VERSION 5.7 ;
  NOWIREEXTENSIONATPIN ON ;
  DIVIDERCHAR "/" ;
  BUSBITCHARS "[]" ;
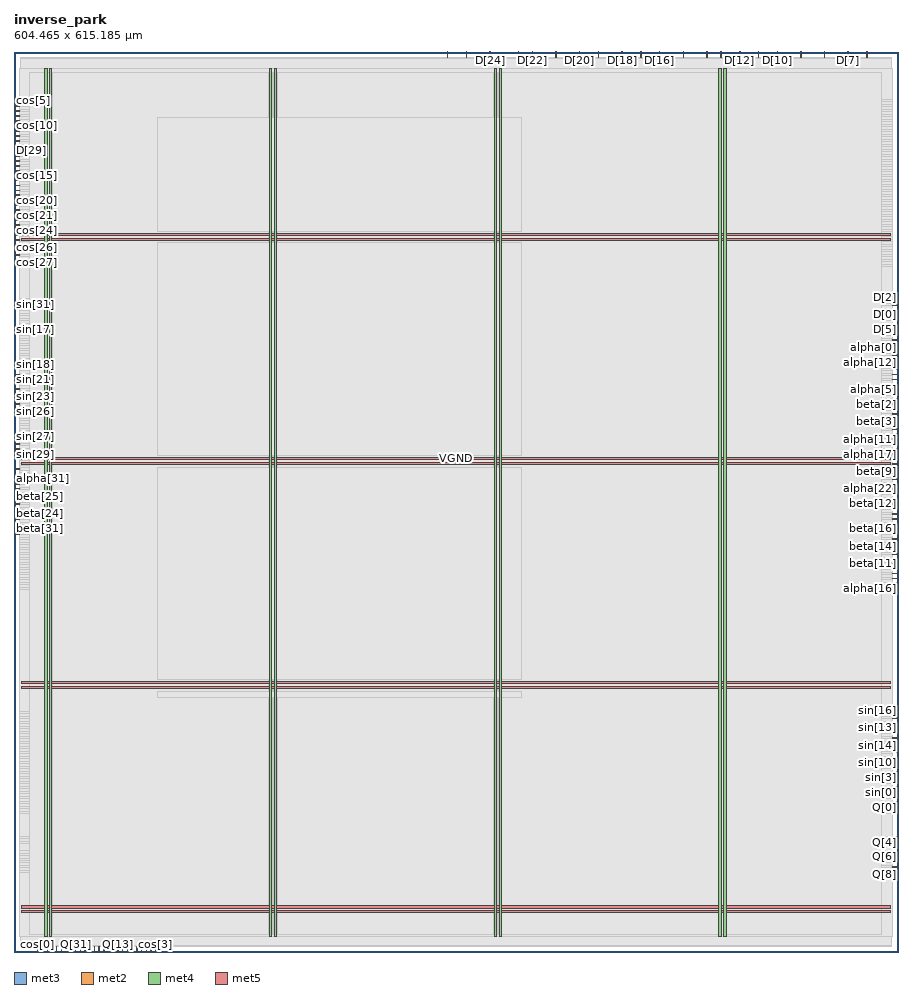
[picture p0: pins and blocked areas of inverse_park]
MACRO inverse_park
  CLASS BLOCK ;
  FOREIGN inverse_park ;
  ORIGIN 0.000 0.000 ;
  SIZE 604.465 BY 615.185 ;
  PIN D[0]
    DIRECTION INPUT ;
    USE SIGNAL ;
    ANTENNAGATEAREA 0.196500 ;
    PORT
      LAYER met3 ;
        RECT 600.465 435.240 604.465 435.840 ;
    END
  END D[0]
  PIN D[10]
    DIRECTION INPUT ;
    USE SIGNAL ;
    ANTENNAGATEAREA 0.159000 ;
    PORT
      LAYER met2 ;
        RECT 521.730 611.185 522.010 615.185 ;
    END
  END D[10]
  PIN D[11]
    DIRECTION INPUT ;
    USE SIGNAL ;
    ANTENNAGATEAREA 0.247500 ;
    PORT
      LAYER met2 ;
        RECT 508.850 611.185 509.130 615.185 ;
    END
  END D[11]
  PIN D[12]
    DIRECTION INPUT ;
    USE SIGNAL ;
    ANTENNAGATEAREA 0.247500 ;
    PORT
      LAYER met2 ;
        RECT 495.970 611.185 496.250 615.185 ;
    END
  END D[12]
  PIN D[13]
    DIRECTION INPUT ;
    USE SIGNAL ;
    ANTENNAGATEAREA 0.159000 ;
    PORT
      LAYER met2 ;
        RECT 483.090 611.185 483.370 615.185 ;
    END
  END D[13]
  PIN D[14]
    DIRECTION INPUT ;
    USE SIGNAL ;
    ANTENNAGATEAREA 0.213000 ;
    PORT
      LAYER met2 ;
        RECT 473.430 611.185 473.710 615.185 ;
    END
  END D[14]
  PIN D[15]
    DIRECTION INPUT ;
    USE SIGNAL ;
    ANTENNAGATEAREA 0.247500 ;
    PORT
      LAYER met2 ;
        RECT 457.330 611.185 457.610 615.185 ;
    END
  END D[15]
  PIN D[16]
    DIRECTION INPUT ;
    USE SIGNAL ;
    ANTENNAGATEAREA 0.159000 ;
    PORT
      LAYER met2 ;
        RECT 441.230 611.185 441.510 615.185 ;
    END
  END D[16]
  PIN D[17]
    DIRECTION INPUT ;
    USE SIGNAL ;
    ANTENNAGATEAREA 0.159000 ;
    PORT
      LAYER met2 ;
        RECT 428.350 611.185 428.630 615.185 ;
    END
  END D[17]
  PIN D[18]
    DIRECTION INPUT ;
    USE SIGNAL ;
    ANTENNAGATEAREA 0.159000 ;
    PORT
      LAYER met2 ;
        RECT 415.470 611.185 415.750 615.185 ;
    END
  END D[18]
  PIN D[19]
    DIRECTION INPUT ;
    USE SIGNAL ;
    ANTENNAGATEAREA 0.213000 ;
    PORT
      LAYER met2 ;
        RECT 399.370 611.185 399.650 615.185 ;
    END
  END D[19]
  PIN D[1]
    DIRECTION INPUT ;
    USE SIGNAL ;
    ANTENNAGATEAREA 0.159000 ;
    PORT
      LAYER met3 ;
        RECT 600.465 431.840 604.465 432.440 ;
    END
  END D[1]
  PIN D[20]
    DIRECTION INPUT ;
    USE SIGNAL ;
    ANTENNAGATEAREA 0.196500 ;
    PORT
      LAYER met2 ;
        RECT 386.490 611.185 386.770 615.185 ;
    END
  END D[20]
  PIN D[21]
    DIRECTION INPUT ;
    USE SIGNAL ;
    ANTENNAGATEAREA 0.196500 ;
    PORT
      LAYER met2 ;
        RECT 370.390 611.185 370.670 615.185 ;
    END
  END D[21]
  PIN D[22]
    DIRECTION INPUT ;
    USE SIGNAL ;
    ANTENNAGATEAREA 0.196500 ;
    PORT
      LAYER met2 ;
        RECT 354.290 611.185 354.570 615.185 ;
    END
  END D[22]
  PIN D[23]
    DIRECTION INPUT ;
    USE SIGNAL ;
    ANTENNAGATEAREA 0.196500 ;
    PORT
      LAYER met2 ;
        RECT 344.630 611.185 344.910 615.185 ;
    END
  END D[23]
  PIN D[24]
    DIRECTION INPUT ;
    USE SIGNAL ;
    ANTENNAGATEAREA 0.213000 ;
    PORT
      LAYER met2 ;
        RECT 325.310 611.185 325.590 615.185 ;
    END
  END D[24]
  PIN D[25]
    DIRECTION INPUT ;
    USE SIGNAL ;
    ANTENNAGATEAREA 0.213000 ;
    PORT
      LAYER met3 ;
        RECT 0.000 578.040 4.000 578.640 ;
    END
  END D[25]
  PIN D[26]
    DIRECTION INPUT ;
    USE SIGNAL ;
    ANTENNAGATEAREA 0.196500 ;
    PORT
      LAYER met3 ;
        RECT 0.000 574.640 4.000 575.240 ;
    END
  END D[26]
  PIN D[27]
    DIRECTION INPUT ;
    USE SIGNAL ;
    ANTENNAGATEAREA 0.196500 ;
    PORT
      LAYER met3 ;
        RECT 0.000 567.840 4.000 568.440 ;
    END
  END D[27]
  PIN D[28]
    DIRECTION INPUT ;
    USE SIGNAL ;
    ANTENNAGATEAREA 0.196500 ;
    PORT
      LAYER met3 ;
        RECT 0.000 557.640 4.000 558.240 ;
    END
  END D[28]
  PIN D[29]
    DIRECTION INPUT ;
    USE SIGNAL ;
    ANTENNAGATEAREA 0.159000 ;
    PORT
      LAYER met3 ;
        RECT 0.000 547.440 4.000 548.040 ;
    END
  END D[29]
  PIN D[2]
    DIRECTION INPUT ;
    USE SIGNAL ;
    ANTENNAGATEAREA 0.213000 ;
    PORT
      LAYER met3 ;
        RECT 600.465 442.040 604.465 442.640 ;
    END
  END D[2]
  PIN D[30]
    DIRECTION INPUT ;
    USE SIGNAL ;
    ANTENNAGATEAREA 0.196500 ;
    PORT
      LAYER met3 ;
        RECT 0.000 537.240 4.000 537.840 ;
    END
  END D[30]
  PIN D[31]
    DIRECTION INPUT ;
    USE SIGNAL ;
    ANTENNAGATEAREA 0.196500 ;
    PORT
      LAYER met3 ;
        RECT 0.000 496.440 4.000 497.040 ;
    END
  END D[31]
  PIN D[3]
    DIRECTION INPUT ;
    USE SIGNAL ;
    ANTENNAGATEAREA 0.213000 ;
    PORT
      LAYER met3 ;
        RECT 600.465 445.440 604.465 446.040 ;
    END
  END D[3]
  PIN D[4]
    DIRECTION INPUT ;
    USE SIGNAL ;
    ANTENNAGATEAREA 0.213000 ;
    PORT
      LAYER met3 ;
        RECT 600.465 438.640 604.465 439.240 ;
    END
  END D[4]
  PIN D[5]
    DIRECTION INPUT ;
    USE SIGNAL ;
    ANTENNAGATEAREA 0.213000 ;
    PORT
      LAYER met3 ;
        RECT 600.465 425.040 604.465 425.640 ;
    END
  END D[5]
  PIN D[6]
    DIRECTION INPUT ;
    USE SIGNAL ;
    ANTENNAGATEAREA 0.196500 ;
    PORT
      LAYER met2 ;
        RECT 582.910 611.185 583.190 615.185 ;
    END
  END D[6]
  PIN D[7]
    DIRECTION INPUT ;
    USE SIGNAL ;
    ANTENNAGATEAREA 0.213000 ;
    PORT
      LAYER met2 ;
        RECT 570.030 611.185 570.310 615.185 ;
    END
  END D[7]
  PIN D[8]
    DIRECTION INPUT ;
    USE SIGNAL ;
    ANTENNAGATEAREA 0.213000 ;
    PORT
      LAYER met2 ;
        RECT 553.930 611.185 554.210 615.185 ;
    END
  END D[8]
  PIN D[9]
    DIRECTION INPUT ;
    USE SIGNAL ;
    ANTENNAGATEAREA 0.213000 ;
    PORT
      LAYER met2 ;
        RECT 537.830 611.185 538.110 615.185 ;
    END
  END D[9]
  PIN Q[0]
    DIRECTION INPUT ;
    USE SIGNAL ;
    ANTENNAGATEAREA 0.196500 ;
    PORT
      LAYER met3 ;
        RECT 600.465 98.640 604.465 99.240 ;
    END
  END Q[0]
  PIN Q[10]
    DIRECTION INPUT ;
    USE SIGNAL ;
    ANTENNAGATEAREA 0.495000 ;
    PORT
      LAYER met3 ;
        RECT 600.465 54.440 604.465 55.040 ;
    END
  END Q[10]
  PIN Q[11]
    DIRECTION INPUT ;
    USE SIGNAL ;
    ANTENNAGATEAREA 0.247500 ;
    PORT
      LAYER met2 ;
        RECT 77.370 0.000 77.650 4.000 ;
    END
  END Q[11]
  PIN Q[12]
    DIRECTION INPUT ;
    USE SIGNAL ;
    ANTENNAGATEAREA 0.247500 ;
    PORT
      LAYER met2 ;
        RECT 80.590 0.000 80.870 4.000 ;
    END
  END Q[12]
  PIN Q[13]
    DIRECTION INPUT ;
    USE SIGNAL ;
    ANTENNAGATEAREA 0.213000 ;
    PORT
      LAYER met2 ;
        RECT 70.930 0.000 71.210 4.000 ;
    END
  END Q[13]
  PIN Q[14]
    DIRECTION INPUT ;
    USE SIGNAL ;
    ANTENNAGATEAREA 0.247500 ;
    PORT
      LAYER met2 ;
        RECT 83.810 0.000 84.090 4.000 ;
    END
  END Q[14]
  PIN Q[15]
    DIRECTION INPUT ;
    USE SIGNAL ;
    ANTENNAGATEAREA 0.213000 ;
    PORT
      LAYER met2 ;
        RECT 74.150 0.000 74.430 4.000 ;
    END
  END Q[15]
  PIN Q[16]
    DIRECTION INPUT ;
    USE SIGNAL ;
    ANTENNAGATEAREA 0.213000 ;
    PORT
      LAYER met2 ;
        RECT 64.490 0.000 64.770 4.000 ;
    END
  END Q[16]
  PIN Q[17]
    DIRECTION INPUT ;
    USE SIGNAL ;
    ANTENNAGATEAREA 0.213000 ;
    PORT
      LAYER met2 ;
        RECT 67.710 0.000 67.990 4.000 ;
    END
  END Q[17]
  PIN Q[18]
    DIRECTION INPUT ;
    USE SIGNAL ;
    ANTENNAGATEAREA 0.196500 ;
    PORT
      LAYER met2 ;
        RECT 87.030 0.000 87.310 4.000 ;
    END
  END Q[18]
  PIN Q[19]
    DIRECTION INPUT ;
    USE SIGNAL ;
    ANTENNAGATEAREA 0.196500 ;
    PORT
      LAYER met2 ;
        RECT 51.610 0.000 51.890 4.000 ;
    END
  END Q[19]
  PIN Q[1]
    DIRECTION INPUT ;
    USE SIGNAL ;
    ANTENNAGATEAREA 0.196500 ;
    PORT
      LAYER met3 ;
        RECT 600.465 102.040 604.465 102.640 ;
    END
  END Q[1]
  PIN Q[20]
    DIRECTION INPUT ;
    USE SIGNAL ;
    ANTENNAGATEAREA 0.196500 ;
    PORT
      LAYER met2 ;
        RECT 48.390 0.000 48.670 4.000 ;
    END
  END Q[20]
  PIN Q[21]
    DIRECTION INPUT ;
    USE SIGNAL ;
    ANTENNAGATEAREA 0.196500 ;
    PORT
      LAYER met2 ;
        RECT 54.830 0.000 55.110 4.000 ;
    END
  END Q[21]
  PIN Q[22]
    DIRECTION INPUT ;
    USE SIGNAL ;
    ANTENNAGATEAREA 0.196500 ;
    PORT
      LAYER met2 ;
        RECT 58.050 0.000 58.330 4.000 ;
    END
  END Q[22]
  PIN Q[23]
    DIRECTION INPUT ;
    USE SIGNAL ;
    ANTENNAGATEAREA 0.196500 ;
    PORT
      LAYER met2 ;
        RECT 61.270 0.000 61.550 4.000 ;
    END
  END Q[23]
  PIN Q[24]
    DIRECTION INPUT ;
    USE SIGNAL ;
    ANTENNAGATEAREA 0.196500 ;
    PORT
      LAYER met2 ;
        RECT 90.250 0.000 90.530 4.000 ;
    END
  END Q[24]
  PIN Q[25]
    DIRECTION INPUT ;
    USE SIGNAL ;
    ANTENNAGATEAREA 0.213000 ;
    PORT
      LAYER met2 ;
        RECT 93.470 0.000 93.750 4.000 ;
    END
  END Q[25]
  PIN Q[26]
    DIRECTION INPUT ;
    USE SIGNAL ;
    ANTENNAGATEAREA 0.196500 ;
    PORT
      LAYER met2 ;
        RECT 35.510 0.000 35.790 4.000 ;
    END
  END Q[26]
  PIN Q[27]
    DIRECTION INPUT ;
    USE SIGNAL ;
    ANTENNAGATEAREA 0.196500 ;
    PORT
      LAYER met2 ;
        RECT 38.730 0.000 39.010 4.000 ;
    END
  END Q[27]
  PIN Q[28]
    DIRECTION INPUT ;
    USE SIGNAL ;
    ANTENNAGATEAREA 0.196500 ;
    PORT
      LAYER met2 ;
        RECT 29.070 0.000 29.350 4.000 ;
    END
  END Q[28]
  PIN Q[29]
    DIRECTION INPUT ;
    USE SIGNAL ;
    ANTENNAGATEAREA 0.213000 ;
    PORT
      LAYER met2 ;
        RECT 25.850 0.000 26.130 4.000 ;
    END
  END Q[29]
  PIN Q[2]
    DIRECTION INPUT ;
    USE SIGNAL ;
    ANTENNAGATEAREA 0.196500 ;
    PORT
      LAYER met3 ;
        RECT 600.465 105.440 604.465 106.040 ;
    END
  END Q[2]
  PIN Q[30]
    DIRECTION INPUT ;
    USE SIGNAL ;
    ANTENNAGATEAREA 0.196500 ;
    PORT
      LAYER met2 ;
        RECT 32.290 0.000 32.570 4.000 ;
    END
  END Q[30]
  PIN Q[31]
    DIRECTION INPUT ;
    USE SIGNAL ;
    ANTENNAGATEAREA 0.159000 ;
    PORT
      LAYER met2 ;
        RECT 41.950 0.000 42.230 4.000 ;
    END
  END Q[31]
  PIN Q[3]
    DIRECTION INPUT ;
    USE SIGNAL ;
    ANTENNAGATEAREA 0.196500 ;
    PORT
      LAYER met3 ;
        RECT 600.465 95.240 604.465 95.840 ;
    END
  END Q[3]
  PIN Q[4]
    DIRECTION INPUT ;
    USE SIGNAL ;
    ANTENNAGATEAREA 0.159000 ;
    PORT
      LAYER met3 ;
        RECT 600.465 74.840 604.465 75.440 ;
    END
  END Q[4]
  PIN Q[5]
    DIRECTION INPUT ;
    USE SIGNAL ;
    ANTENNAGATEAREA 0.196500 ;
    PORT
      LAYER met3 ;
        RECT 600.465 78.240 604.465 78.840 ;
    END
  END Q[5]
  PIN Q[6]
    DIRECTION INPUT ;
    USE SIGNAL ;
    ANTENNAGATEAREA 0.247500 ;
    PORT
      LAYER met3 ;
        RECT 600.465 64.640 604.465 65.240 ;
    END
  END Q[6]
  PIN Q[7]
    DIRECTION INPUT ;
    USE SIGNAL ;
    ANTENNAGATEAREA 0.247500 ;
    PORT
      LAYER met3 ;
        RECT 600.465 61.240 604.465 61.840 ;
    END
  END Q[7]
  PIN Q[8]
    DIRECTION INPUT ;
    USE SIGNAL ;
    ANTENNAGATEAREA 0.247500 ;
    PORT
      LAYER met3 ;
        RECT 600.465 57.840 604.465 58.440 ;
    END
  END Q[8]
  PIN Q[9]
    DIRECTION INPUT ;
    USE SIGNAL ;
    ANTENNAGATEAREA 0.247500 ;
    PORT
      LAYER met3 ;
        RECT 600.465 68.040 604.465 68.640 ;
    END
  END Q[9]
  PIN VGND
    DIRECTION INOUT ;
    USE GROUND ;
    PORT
      LAYER met4 ;
        RECT 24.340 10.640 25.940 604.080 ;
    END
    PORT
      LAYER met4 ;
        RECT 177.940 10.640 179.540 604.080 ;
    END
    PORT
      LAYER met4 ;
        RECT 331.540 10.640 333.140 604.080 ;
    END
    PORT
      LAYER met4 ;
        RECT 485.140 10.640 486.740 604.080 ;
    END
    PORT
      LAYER met5 ;
        RECT 5.280 30.030 599.160 31.630 ;
    END
    PORT
      LAYER met5 ;
        RECT 5.280 183.210 599.160 184.810 ;
    END
    PORT
      LAYER met5 ;
        RECT 5.280 336.390 599.160 337.990 ;
    END
    PORT
      LAYER met5 ;
        RECT 5.280 489.570 599.160 491.170 ;
    END
  END VGND
  PIN VPWR
    DIRECTION INOUT ;
    USE POWER ;
    PORT
      LAYER met4 ;
        RECT 21.040 10.640 22.640 604.080 ;
    END
    PORT
      LAYER met4 ;
        RECT 174.640 10.640 176.240 604.080 ;
    END
    PORT
      LAYER met4 ;
        RECT 328.240 10.640 329.840 604.080 ;
    END
    PORT
      LAYER met4 ;
        RECT 481.840 10.640 483.440 604.080 ;
    END
    PORT
      LAYER met5 ;
        RECT 5.280 26.730 599.160 28.330 ;
    END
    PORT
      LAYER met5 ;
        RECT 5.280 179.910 599.160 181.510 ;
    END
    PORT
      LAYER met5 ;
        RECT 5.280 333.090 599.160 334.690 ;
    END
    PORT
      LAYER met5 ;
        RECT 5.280 486.270 599.160 487.870 ;
    END
  END VPWR
  PIN alpha[0]
    DIRECTION OUTPUT ;
    USE SIGNAL ;
    ANTENNADIFFAREA 0.445500 ;
    PORT
      LAYER met3 ;
        RECT 600.465 418.240 604.465 418.840 ;
    END
  END alpha[0]
  PIN alpha[10]
    DIRECTION OUTPUT ;
    USE SIGNAL ;
    ANTENNADIFFAREA 0.795200 ;
    PORT
      LAYER met3 ;
        RECT 600.465 360.440 604.465 361.040 ;
    END
  END alpha[10]
  PIN alpha[11]
    DIRECTION OUTPUT ;
    USE SIGNAL ;
    ANTENNADIFFAREA 0.445500 ;
    PORT
      LAYER met3 ;
        RECT 600.465 350.240 604.465 350.840 ;
    END
  END alpha[11]
  PIN alpha[12]
    DIRECTION OUTPUT ;
    USE SIGNAL ;
    ANTENNADIFFAREA 0.795200 ;
    PORT
      LAYER met3 ;
        RECT 600.465 408.040 604.465 408.640 ;
    END
  END alpha[12]
  PIN alpha[13]
    DIRECTION OUTPUT ;
    USE SIGNAL ;
    ANTENNADIFFAREA 0.445500 ;
    PORT
      LAYER met3 ;
        RECT 600.465 397.840 604.465 398.440 ;
    END
  END alpha[13]
  PIN alpha[14]
    DIRECTION OUTPUT ;
    USE SIGNAL ;
    ANTENNADIFFAREA 0.795200 ;
    PORT
      LAYER met3 ;
        RECT 600.465 346.840 604.465 347.440 ;
    END
  END alpha[14]
  PIN alpha[15]
    DIRECTION OUTPUT ;
    USE SIGNAL ;
    ANTENNADIFFAREA 0.795200 ;
    PORT
      LAYER met3 ;
        RECT 600.465 329.840 604.465 330.440 ;
    END
  END alpha[15]
  PIN alpha[16]
    DIRECTION OUTPUT ;
    USE SIGNAL ;
    ANTENNADIFFAREA 0.445500 ;
    PORT
      LAYER met3 ;
        RECT 600.465 248.240 604.465 248.840 ;
    END
  END alpha[16]
  PIN alpha[17]
    DIRECTION OUTPUT ;
    USE SIGNAL ;
    ANTENNADIFFAREA 0.445500 ;
    PORT
      LAYER met3 ;
        RECT 600.465 340.040 604.465 340.640 ;
    END
  END alpha[17]
  PIN alpha[18]
    DIRECTION OUTPUT ;
    USE SIGNAL ;
    ANTENNADIFFAREA 0.445500 ;
    PORT
      LAYER met3 ;
        RECT 600.465 336.640 604.465 337.240 ;
    END
  END alpha[18]
  PIN alpha[19]
    DIRECTION OUTPUT ;
    USE SIGNAL ;
    ANTENNADIFFAREA 0.795200 ;
    PORT
      LAYER met3 ;
        RECT 600.465 255.040 604.465 255.640 ;
    END
  END alpha[19]
  PIN alpha[1]
    DIRECTION OUTPUT ;
    USE SIGNAL ;
    ANTENNADIFFAREA 0.445500 ;
    PORT
      LAYER met3 ;
        RECT 600.465 394.440 604.465 395.040 ;
    END
  END alpha[1]
  PIN alpha[20]
    DIRECTION OUTPUT ;
    USE SIGNAL ;
    ANTENNADIFFAREA 0.445500 ;
    PORT
      LAYER met3 ;
        RECT 600.465 258.440 604.465 259.040 ;
    END
  END alpha[20]
  PIN alpha[21]
    DIRECTION OUTPUT ;
    USE SIGNAL ;
    ANTENNADIFFAREA 0.445500 ;
    PORT
      LAYER met3 ;
        RECT 600.465 251.640 604.465 252.240 ;
    END
  END alpha[21]
  PIN alpha[22]
    DIRECTION OUTPUT ;
    USE SIGNAL ;
    ANTENNADIFFAREA 0.445500 ;
    PORT
      LAYER met3 ;
        RECT 600.465 316.240 604.465 316.840 ;
    END
  END alpha[22]
  PIN alpha[23]
    DIRECTION OUTPUT ;
    USE SIGNAL ;
    ANTENNADIFFAREA 0.445500 ;
    PORT
      LAYER met3 ;
        RECT 600.465 261.840 604.465 262.440 ;
    END
  END alpha[23]
  PIN alpha[24]
    DIRECTION OUTPUT ;
    USE SIGNAL ;
    ANTENNADIFFAREA 0.795200 ;
    PORT
      LAYER met2 ;
        RECT 309.210 611.185 309.490 615.185 ;
    END
  END alpha[24]
  PIN alpha[25]
    DIRECTION OUTPUT ;
    USE SIGNAL ;
    ANTENNADIFFAREA 0.445500 ;
    PORT
      LAYER met3 ;
        RECT 600.465 268.640 604.465 269.240 ;
    END
  END alpha[25]
  PIN alpha[26]
    DIRECTION OUTPUT ;
    USE SIGNAL ;
    ANTENNADIFFAREA 0.795200 ;
    PORT
      LAYER met3 ;
        RECT 0.000 295.840 4.000 296.440 ;
    END
  END alpha[26]
  PIN alpha[27]
    DIRECTION OUTPUT ;
    USE SIGNAL ;
    ANTENNADIFFAREA 0.795200 ;
    PORT
      LAYER met2 ;
        RECT 296.330 611.185 296.610 615.185 ;
    END
  END alpha[27]
  PIN alpha[28]
    DIRECTION OUTPUT ;
    USE SIGNAL ;
    ANTENNADIFFAREA 0.795200 ;
    PORT
      LAYER met3 ;
        RECT 0.000 309.440 4.000 310.040 ;
    END
  END alpha[28]
  PIN alpha[29]
    DIRECTION OUTPUT ;
    USE SIGNAL ;
    ANTENNADIFFAREA 0.795200 ;
    PORT
      LAYER met3 ;
        RECT 0.000 319.640 4.000 320.240 ;
    END
  END alpha[29]
  PIN alpha[2]
    DIRECTION OUTPUT ;
    USE SIGNAL ;
    ANTENNADIFFAREA 0.795200 ;
    PORT
      LAYER met3 ;
        RECT 600.465 404.640 604.465 405.240 ;
    END
  END alpha[2]
  PIN alpha[30]
    DIRECTION OUTPUT ;
    USE SIGNAL ;
    ANTENNADIFFAREA 0.795200 ;
    PORT
      LAYER met3 ;
        RECT 0.000 329.840 4.000 330.440 ;
    END
  END alpha[30]
  PIN alpha[31]
    DIRECTION OUTPUT ;
    USE SIGNAL ;
    ANTENNADIFFAREA 0.795200 ;
    PORT
      LAYER met3 ;
        RECT 0.000 323.040 4.000 323.640 ;
    END
  END alpha[31]
  PIN alpha[3]
    DIRECTION OUTPUT ;
    USE SIGNAL ;
    ANTENNADIFFAREA 0.445500 ;
    PORT
      LAYER met3 ;
        RECT 600.465 414.840 604.465 415.440 ;
    END
  END alpha[3]
  PIN alpha[4]
    DIRECTION OUTPUT ;
    USE SIGNAL ;
    ANTENNADIFFAREA 0.445500 ;
    PORT
      LAYER met3 ;
        RECT 600.465 380.840 604.465 381.440 ;
    END
  END alpha[4]
  PIN alpha[5]
    DIRECTION OUTPUT ;
    USE SIGNAL ;
    ANTENNADIFFAREA 0.795200 ;
    PORT
      LAYER met3 ;
        RECT 600.465 384.240 604.465 384.840 ;
    END
  END alpha[5]
  PIN alpha[6]
    DIRECTION OUTPUT ;
    USE SIGNAL ;
    ANTENNADIFFAREA 0.795200 ;
    PORT
      LAYER met3 ;
        RECT 600.465 377.440 604.465 378.040 ;
    END
  END alpha[6]
  PIN alpha[7]
    DIRECTION OUTPUT ;
    USE SIGNAL ;
    ANTENNADIFFAREA 0.445500 ;
    PORT
      LAYER met3 ;
        RECT 600.465 387.640 604.465 388.240 ;
    END
  END alpha[7]
  PIN alpha[8]
    DIRECTION OUTPUT ;
    USE SIGNAL ;
    ANTENNADIFFAREA 0.795200 ;
    PORT
      LAYER met3 ;
        RECT 600.465 363.840 604.465 364.440 ;
    END
  END alpha[8]
  PIN alpha[9]
    DIRECTION OUTPUT ;
    USE SIGNAL ;
    ANTENNADIFFAREA 0.795200 ;
    PORT
      LAYER met3 ;
        RECT 600.465 401.240 604.465 401.840 ;
    END
  END alpha[9]
  PIN beta[0]
    DIRECTION OUTPUT ;
    USE SIGNAL ;
    ANTENNADIFFAREA 0.795200 ;
    PORT
      LAYER met3 ;
        RECT 600.465 411.440 604.465 412.040 ;
    END
  END beta[0]
  PIN beta[10]
    DIRECTION OUTPUT ;
    USE SIGNAL ;
    ANTENNADIFFAREA 0.795200 ;
    PORT
      LAYER met3 ;
        RECT 600.465 319.640 604.465 320.240 ;
    END
  END beta[10]
  PIN beta[11]
    DIRECTION OUTPUT ;
    USE SIGNAL ;
    ANTENNADIFFAREA 0.445500 ;
    PORT
      LAYER met3 ;
        RECT 600.465 265.240 604.465 265.840 ;
    END
  END beta[11]
  PIN beta[12]
    DIRECTION OUTPUT ;
    USE SIGNAL ;
    ANTENNADIFFAREA 0.795200 ;
    PORT
      LAYER met3 ;
        RECT 600.465 306.040 604.465 306.640 ;
    END
  END beta[12]
  PIN beta[13]
    DIRECTION OUTPUT ;
    USE SIGNAL ;
    ANTENNADIFFAREA 0.795200 ;
    PORT
      LAYER met3 ;
        RECT 600.465 309.440 604.465 310.040 ;
    END
  END beta[13]
  PIN beta[14]
    DIRECTION OUTPUT ;
    USE SIGNAL ;
    ANTENNADIFFAREA 0.445500 ;
    PORT
      LAYER met3 ;
        RECT 600.465 272.040 604.465 272.640 ;
    END
  END beta[14]
  PIN beta[15]
    DIRECTION OUTPUT ;
    USE SIGNAL ;
    ANTENNADIFFAREA 0.795200 ;
    PORT
      LAYER met3 ;
        RECT 600.465 278.840 604.465 279.440 ;
    END
  END beta[15]
  PIN beta[16]
    DIRECTION OUTPUT ;
    USE SIGNAL ;
    ANTENNADIFFAREA 0.445500 ;
    PORT
      LAYER met3 ;
        RECT 600.465 289.040 604.465 289.640 ;
    END
  END beta[16]
  PIN beta[17]
    DIRECTION OUTPUT ;
    USE SIGNAL ;
    ANTENNADIFFAREA 0.445500 ;
    PORT
      LAYER met3 ;
        RECT 600.465 285.640 604.465 286.240 ;
    END
  END beta[17]
  PIN beta[18]
    DIRECTION OUTPUT ;
    USE SIGNAL ;
    ANTENNADIFFAREA 0.795200 ;
    PORT
      LAYER met3 ;
        RECT 600.465 282.240 604.465 282.840 ;
    END
  END beta[18]
  PIN beta[19]
    DIRECTION OUTPUT ;
    USE SIGNAL ;
    ANTENNADIFFAREA 0.795200 ;
    PORT
      LAYER met3 ;
        RECT 600.465 299.240 604.465 299.840 ;
    END
  END beta[19]
  PIN beta[1]
    DIRECTION OUTPUT ;
    USE SIGNAL ;
    ANTENNADIFFAREA 0.445500 ;
    PORT
      LAYER met3 ;
        RECT 600.465 391.040 604.465 391.640 ;
    END
  END beta[1]
  PIN beta[20]
    DIRECTION OUTPUT ;
    USE SIGNAL ;
    ANTENNADIFFAREA 0.795200 ;
    PORT
      LAYER met3 ;
        RECT 600.465 302.640 604.465 303.240 ;
    END
  END beta[20]
  PIN beta[21]
    DIRECTION OUTPUT ;
    USE SIGNAL ;
    ANTENNADIFFAREA 0.795200 ;
    PORT
      LAYER met3 ;
        RECT 600.465 292.440 604.465 293.040 ;
    END
  END beta[21]
  PIN beta[22]
    DIRECTION OUTPUT ;
    USE SIGNAL ;
    ANTENNADIFFAREA 0.795200 ;
    PORT
      LAYER met3 ;
        RECT 600.465 275.440 604.465 276.040 ;
    END
  END beta[22]
  PIN beta[23]
    DIRECTION OUTPUT ;
    USE SIGNAL ;
    ANTENNADIFFAREA 0.795200 ;
    PORT
      LAYER met3 ;
        RECT 600.465 295.840 604.465 296.440 ;
    END
  END beta[23]
  PIN beta[24]
    DIRECTION OUTPUT ;
    USE SIGNAL ;
    ANTENNADIFFAREA 0.795200 ;
    PORT
      LAYER met3 ;
        RECT 0.000 299.240 4.000 299.840 ;
    END
  END beta[24]
  PIN beta[25]
    DIRECTION OUTPUT ;
    USE SIGNAL ;
    ANTENNADIFFAREA 0.795200 ;
    PORT
      LAYER met3 ;
        RECT 0.000 306.040 4.000 306.640 ;
    END
  END beta[25]
  PIN beta[26]
    DIRECTION OUTPUT ;
    USE SIGNAL ;
    ANTENNADIFFAREA 0.795200 ;
    PORT
      LAYER met3 ;
        RECT 0.000 312.840 4.000 313.440 ;
    END
  END beta[26]
  PIN beta[27]
    DIRECTION OUTPUT ;
    USE SIGNAL ;
    ANTENNADIFFAREA 0.795200 ;
    PORT
      LAYER met3 ;
        RECT 0.000 292.440 4.000 293.040 ;
    END
  END beta[27]
  PIN beta[28]
    DIRECTION OUTPUT ;
    USE SIGNAL ;
    ANTENNADIFFAREA 0.795200 ;
    PORT
      LAYER met3 ;
        RECT 0.000 285.640 4.000 286.240 ;
    END
  END beta[28]
  PIN beta[29]
    DIRECTION OUTPUT ;
    USE SIGNAL ;
    ANTENNADIFFAREA 0.795200 ;
    PORT
      LAYER met3 ;
        RECT 0.000 316.240 4.000 316.840 ;
    END
  END beta[29]
  PIN beta[2]
    DIRECTION OUTPUT ;
    USE SIGNAL ;
    ANTENNADIFFAREA 0.445500 ;
    PORT
      LAYER met3 ;
        RECT 600.465 374.040 604.465 374.640 ;
    END
  END beta[2]
  PIN beta[30]
    DIRECTION OUTPUT ;
    USE SIGNAL ;
    ANTENNADIFFAREA 0.795200 ;
    PORT
      LAYER met3 ;
        RECT 0.000 302.640 4.000 303.240 ;
    END
  END beta[30]
  PIN beta[31]
    DIRECTION OUTPUT ;
    USE SIGNAL ;
    ANTENNADIFFAREA 0.795200 ;
    PORT
      LAYER met3 ;
        RECT 0.000 289.040 4.000 289.640 ;
    END
  END beta[31]
  PIN beta[3]
    DIRECTION OUTPUT ;
    USE SIGNAL ;
    ANTENNADIFFAREA 0.795200 ;
    PORT
      LAYER met3 ;
        RECT 600.465 367.240 604.465 367.840 ;
    END
  END beta[3]
  PIN beta[4]
    DIRECTION OUTPUT ;
    USE SIGNAL ;
    ANTENNADIFFAREA 0.795200 ;
    PORT
      LAYER met3 ;
        RECT 600.465 353.640 604.465 354.240 ;
    END
  END beta[4]
  PIN beta[5]
    DIRECTION OUTPUT ;
    USE SIGNAL ;
    ANTENNADIFFAREA 0.795200 ;
    PORT
      LAYER met3 ;
        RECT 600.465 357.040 604.465 357.640 ;
    END
  END beta[5]
  PIN beta[6]
    DIRECTION OUTPUT ;
    USE SIGNAL ;
    ANTENNADIFFAREA 0.795200 ;
    PORT
      LAYER met3 ;
        RECT 600.465 370.640 604.465 371.240 ;
    END
  END beta[6]
  PIN beta[7]
    DIRECTION OUTPUT ;
    USE SIGNAL ;
    ANTENNADIFFAREA 0.795200 ;
    PORT
      LAYER met3 ;
        RECT 600.465 343.440 604.465 344.040 ;
    END
  END beta[7]
  PIN beta[8]
    DIRECTION OUTPUT ;
    USE SIGNAL ;
    ANTENNADIFFAREA 0.795200 ;
    PORT
      LAYER met3 ;
        RECT 600.465 326.440 604.465 327.040 ;
    END
  END beta[8]
  PIN beta[9]
    DIRECTION OUTPUT ;
    USE SIGNAL ;
    ANTENNADIFFAREA 0.795200 ;
    PORT
      LAYER met3 ;
        RECT 600.465 333.240 604.465 333.840 ;
    END
  END beta[9]
  PIN clk
    DIRECTION INPUT ;
    USE SIGNAL ;
    ANTENNAGATEAREA 0.852000 ;
    PORT
      LAYER met3 ;
        RECT 600.465 428.440 604.465 429.040 ;
    END
  END clk
  PIN cos[0]
    DIRECTION INPUT ;
    USE SIGNAL ;
    ANTENNAGATEAREA 0.495000 ;
    PORT
      LAYER met2 ;
        RECT 16.190 0.000 16.470 4.000 ;
    END
  END cos[0]
  PIN cos[10]
    DIRECTION INPUT ;
    USE SIGNAL ;
    ANTENNAGATEAREA 0.213000 ;
    PORT
      LAYER met3 ;
        RECT 0.000 564.440 4.000 565.040 ;
    END
  END cos[10]
  PIN cos[11]
    DIRECTION INPUT ;
    USE SIGNAL ;
    ANTENNAGATEAREA 0.426000 ;
    PORT
      LAYER met3 ;
        RECT 0.000 561.040 4.000 561.640 ;
    END
  END cos[11]
  PIN cos[12]
    DIRECTION INPUT ;
    USE SIGNAL ;
    ANTENNAGATEAREA 0.213000 ;
    PORT
      LAYER met3 ;
        RECT 0.000 544.040 4.000 544.640 ;
    END
  END cos[12]
  PIN cos[13]
    DIRECTION INPUT ;
    USE SIGNAL ;
    ANTENNAGATEAREA 0.196500 ;
    PORT
      LAYER met3 ;
        RECT 0.000 540.640 4.000 541.240 ;
    END
  END cos[13]
  PIN cos[14]
    DIRECTION INPUT ;
    USE SIGNAL ;
    ANTENNAGATEAREA 0.196500 ;
    PORT
      LAYER met3 ;
        RECT 0.000 533.840 4.000 534.440 ;
    END
  END cos[14]
  PIN cos[15]
    DIRECTION INPUT ;
    USE SIGNAL ;
    ANTENNAGATEAREA 0.196500 ;
    PORT
      LAYER met3 ;
        RECT 0.000 530.440 4.000 531.040 ;
    END
  END cos[15]
  PIN cos[16]
    DIRECTION INPUT ;
    USE SIGNAL ;
    ANTENNAGATEAREA 0.159000 ;
    PORT
      LAYER met3 ;
        RECT 0.000 527.040 4.000 527.640 ;
    END
  END cos[16]
  PIN cos[17]
    DIRECTION INPUT ;
    USE SIGNAL ;
    ANTENNAGATEAREA 0.159000 ;
    PORT
      LAYER met3 ;
        RECT 0.000 523.640 4.000 524.240 ;
    END
  END cos[17]
  PIN cos[18]
    DIRECTION INPUT ;
    USE SIGNAL ;
    ANTENNAGATEAREA 0.159000 ;
    PORT
      LAYER met3 ;
        RECT 0.000 520.240 4.000 520.840 ;
    END
  END cos[18]
  PIN cos[19]
    DIRECTION INPUT ;
    USE SIGNAL ;
    ANTENNAGATEAREA 0.196500 ;
    PORT
      LAYER met3 ;
        RECT 0.000 516.840 4.000 517.440 ;
    END
  END cos[19]
  PIN cos[1]
    DIRECTION INPUT ;
    USE SIGNAL ;
    ANTENNAGATEAREA 0.495000 ;
    PORT
      LAYER met2 ;
        RECT 22.630 0.000 22.910 4.000 ;
    END
  END cos[1]
  PIN cos[20]
    DIRECTION INPUT ;
    USE SIGNAL ;
    ANTENNAGATEAREA 0.196500 ;
    PORT
      LAYER met3 ;
        RECT 0.000 513.440 4.000 514.040 ;
    END
  END cos[20]
  PIN cos[21]
    DIRECTION INPUT ;
    USE SIGNAL ;
    ANTENNAGATEAREA 0.159000 ;
    PORT
      LAYER met3 ;
        RECT 0.000 503.240 4.000 503.840 ;
    END
  END cos[21]
  PIN cos[22]
    DIRECTION INPUT ;
    USE SIGNAL ;
    ANTENNAGATEAREA 0.196500 ;
    PORT
      LAYER met3 ;
        RECT 0.000 506.640 4.000 507.240 ;
    END
  END cos[22]
  PIN cos[23]
    DIRECTION INPUT ;
    USE SIGNAL ;
    ANTENNAGATEAREA 0.213000 ;
    PORT
      LAYER met3 ;
        RECT 0.000 499.840 4.000 500.440 ;
    END
  END cos[23]
  PIN cos[24]
    DIRECTION INPUT ;
    USE SIGNAL ;
    ANTENNAGATEAREA 0.196500 ;
    PORT
      LAYER met3 ;
        RECT 0.000 493.040 4.000 493.640 ;
    END
  END cos[24]
  PIN cos[25]
    DIRECTION INPUT ;
    USE SIGNAL ;
    ANTENNAGATEAREA 0.196500 ;
    PORT
      LAYER met3 ;
        RECT 0.000 489.640 4.000 490.240 ;
    END
  END cos[25]
  PIN cos[26]
    DIRECTION INPUT ;
    USE SIGNAL ;
    ANTENNAGATEAREA 0.159000 ;
    PORT
      LAYER met3 ;
        RECT 0.000 486.240 4.000 486.840 ;
    END
  END cos[26]
  PIN cos[27]
    DIRECTION INPUT ;
    USE SIGNAL ;
    ANTENNAGATEAREA 0.213000 ;
    PORT
      LAYER met3 ;
        RECT 0.000 476.040 4.000 476.640 ;
    END
  END cos[27]
  PIN cos[28]
    DIRECTION INPUT ;
    USE SIGNAL ;
    ANTENNAGATEAREA 0.213000 ;
    PORT
      LAYER met3 ;
        RECT 0.000 472.640 4.000 473.240 ;
    END
  END cos[28]
  PIN cos[29]
    DIRECTION INPUT ;
    USE SIGNAL ;
    ANTENNAGATEAREA 0.159000 ;
    PORT
      LAYER met3 ;
        RECT 0.000 469.240 4.000 469.840 ;
    END
  END cos[29]
  PIN cos[2]
    DIRECTION INPUT ;
    USE SIGNAL ;
    ANTENNAGATEAREA 0.495000 ;
    PORT
      LAYER met2 ;
        RECT 45.170 0.000 45.450 4.000 ;
    END
  END cos[2]
  PIN cos[30]
    DIRECTION INPUT ;
    USE SIGNAL ;
    ANTENNAGATEAREA 0.196500 ;
    PORT
      LAYER met3 ;
        RECT 0.000 479.440 4.000 480.040 ;
    END
  END cos[30]
  PIN cos[31]
    DIRECTION INPUT ;
    USE SIGNAL ;
    ANTENNAGATEAREA 0.196500 ;
    PORT
      LAYER met3 ;
        RECT 0.000 510.040 4.000 510.640 ;
    END
  END cos[31]
  PIN cos[3]
    DIRECTION INPUT ;
    USE SIGNAL ;
    ANTENNAGATEAREA 0.426000 ;
    PORT
      LAYER met2 ;
        RECT 96.690 0.000 96.970 4.000 ;
    END
  END cos[3]
  PIN cos[4]
    DIRECTION INPUT ;
    USE SIGNAL ;
    ANTENNAGATEAREA 0.247500 ;
    PORT
      LAYER met2 ;
        RECT 19.410 0.000 19.690 4.000 ;
    END
  END cos[4]
  PIN cos[5]
    DIRECTION INPUT ;
    USE SIGNAL ;
    ANTENNAGATEAREA 0.213000 ;
    PORT
      LAYER met3 ;
        RECT 0.000 581.440 4.000 582.040 ;
    END
  END cos[5]
  PIN cos[6]
    DIRECTION INPUT ;
    USE SIGNAL ;
    ANTENNAGATEAREA 0.213000 ;
    PORT
      LAYER met3 ;
        RECT 0.000 571.240 4.000 571.840 ;
    END
  END cos[6]
  PIN cos[7]
    DIRECTION INPUT ;
    USE SIGNAL ;
    ANTENNAGATEAREA 0.213000 ;
    PORT
      LAYER met3 ;
        RECT 0.000 554.240 4.000 554.840 ;
    END
  END cos[7]
  PIN cos[8]
    DIRECTION INPUT ;
    USE SIGNAL ;
    ANTENNAGATEAREA 0.213000 ;
    PORT
      LAYER met3 ;
        RECT 0.000 550.840 4.000 551.440 ;
    END
  END cos[8]
  PIN cos[9]
    DIRECTION INPUT ;
    USE SIGNAL ;
    ANTENNAGATEAREA 0.213000 ;
    PORT
      LAYER met3 ;
        RECT 0.000 482.840 4.000 483.440 ;
    END
  END cos[9]
  PIN done
    DIRECTION OUTPUT ;
    USE SIGNAL ;
    ANTENNADIFFAREA 0.445500 ;
    PORT
      LAYER met3 ;
        RECT 600.465 312.840 604.465 313.440 ;
    END
  END done
  PIN rstb
    DIRECTION INPUT ;
    USE SIGNAL ;
    ANTENNAGATEAREA 0.196500 ;
    PORT
      LAYER met3 ;
        RECT 600.465 421.640 604.465 422.240 ;
    END
  END rstb
  PIN sin[0]
    DIRECTION INPUT ;
    USE SIGNAL ;
    ANTENNAGATEAREA 0.495000 ;
    PORT
      LAYER met3 ;
        RECT 600.465 108.840 604.465 109.440 ;
    END
  END sin[0]
  PIN sin[10]
    DIRECTION INPUT ;
    USE SIGNAL ;
    ANTENNAGATEAREA 0.213000 ;
    PORT
      LAYER met3 ;
        RECT 600.465 129.240 604.465 129.840 ;
    END
  END sin[10]
  PIN sin[11]
    DIRECTION INPUT ;
    USE SIGNAL ;
    ANTENNAGATEAREA 0.426000 ;
    PORT
      LAYER met3 ;
        RECT 600.465 132.640 604.465 133.240 ;
    END
  END sin[11]
  PIN sin[12]
    DIRECTION INPUT ;
    USE SIGNAL ;
    ANTENNAGATEAREA 0.196500 ;
    PORT
      LAYER met3 ;
        RECT 600.465 149.640 604.465 150.240 ;
    END
  END sin[12]
  PIN sin[13]
    DIRECTION INPUT ;
    USE SIGNAL ;
    ANTENNAGATEAREA 0.126000 ;
    PORT
      LAYER met3 ;
        RECT 600.465 153.040 604.465 153.640 ;
    END
  END sin[13]
  PIN sin[14]
    DIRECTION INPUT ;
    USE SIGNAL ;
    ANTENNAGATEAREA 0.213000 ;
    PORT
      LAYER met3 ;
        RECT 600.465 146.240 604.465 146.840 ;
    END
  END sin[14]
  PIN sin[15]
    DIRECTION INPUT ;
    USE SIGNAL ;
    ANTENNAGATEAREA 0.495000 ;
    PORT
      LAYER met3 ;
        RECT 600.465 156.440 604.465 157.040 ;
    END
  END sin[15]
  PIN sin[16]
    DIRECTION INPUT ;
    USE SIGNAL ;
    ANTENNAGATEAREA 0.426000 ;
    PORT
      LAYER met3 ;
        RECT 600.465 159.840 604.465 160.440 ;
    END
  END sin[16]
  PIN sin[17]
    DIRECTION INPUT ;
    USE SIGNAL ;
    ANTENNAGATEAREA 0.196500 ;
    PORT
      LAYER met3 ;
        RECT 0.000 425.040 4.000 425.640 ;
    END
  END sin[17]
  PIN sin[18]
    DIRECTION INPUT ;
    USE SIGNAL ;
    ANTENNAGATEAREA 0.196500 ;
    PORT
      LAYER met3 ;
        RECT 0.000 401.240 4.000 401.840 ;
    END
  END sin[18]
  PIN sin[19]
    DIRECTION INPUT ;
    USE SIGNAL ;
    ANTENNAGATEAREA 0.247500 ;
    PORT
      LAYER met3 ;
        RECT 0.000 397.840 4.000 398.440 ;
    END
  END sin[19]
  PIN sin[1]
    DIRECTION INPUT ;
    USE SIGNAL ;
    ANTENNAGATEAREA 0.742500 ;
    PORT
      LAYER met3 ;
        RECT 600.465 112.240 604.465 112.840 ;
    END
  END sin[1]
  PIN sin[20]
    DIRECTION INPUT ;
    USE SIGNAL ;
    ANTENNAGATEAREA 0.159000 ;
    PORT
      LAYER met3 ;
        RECT 0.000 394.440 4.000 395.040 ;
    END
  END sin[20]
  PIN sin[21]
    DIRECTION INPUT ;
    USE SIGNAL ;
    ANTENNAGATEAREA 0.196500 ;
    PORT
      LAYER met3 ;
        RECT 0.000 391.040 4.000 391.640 ;
    END
  END sin[21]
  PIN sin[22]
    DIRECTION INPUT ;
    USE SIGNAL ;
    ANTENNAGATEAREA 0.196500 ;
    PORT
      LAYER met3 ;
        RECT 0.000 387.640 4.000 388.240 ;
    END
  END sin[22]
  PIN sin[23]
    DIRECTION INPUT ;
    USE SIGNAL ;
    ANTENNAGATEAREA 0.213000 ;
    PORT
      LAYER met3 ;
        RECT 0.000 384.240 4.000 384.840 ;
    END
  END sin[23]
  PIN sin[24]
    DIRECTION INPUT ;
    USE SIGNAL ;
    ANTENNAGATEAREA 0.196500 ;
    PORT
      LAYER met3 ;
        RECT 0.000 380.840 4.000 381.440 ;
    END
  END sin[24]
  PIN sin[25]
    DIRECTION INPUT ;
    USE SIGNAL ;
    ANTENNAGATEAREA 0.196500 ;
    PORT
      LAYER met3 ;
        RECT 0.000 377.440 4.000 378.040 ;
    END
  END sin[25]
  PIN sin[26]
    DIRECTION INPUT ;
    USE SIGNAL ;
    ANTENNAGATEAREA 0.196500 ;
    PORT
      LAYER met3 ;
        RECT 0.000 374.040 4.000 374.640 ;
    END
  END sin[26]
  PIN sin[27]
    DIRECTION INPUT ;
    USE SIGNAL ;
    ANTENNAGATEAREA 0.196500 ;
    PORT
      LAYER met3 ;
        RECT 0.000 346.840 4.000 347.440 ;
    END
  END sin[27]
  PIN sin[28]
    DIRECTION INPUT ;
    USE SIGNAL ;
    ANTENNAGATEAREA 0.159000 ;
    PORT
      LAYER met3 ;
        RECT 0.000 343.440 4.000 344.040 ;
    END
  END sin[28]
  PIN sin[29]
    DIRECTION INPUT ;
    USE SIGNAL ;
    ANTENNAGATEAREA 0.159000 ;
    PORT
      LAYER met3 ;
        RECT 0.000 340.040 4.000 340.640 ;
    END
  END sin[29]
  PIN sin[2]
    DIRECTION INPUT ;
    USE SIGNAL ;
    ANTENNAGATEAREA 0.196500 ;
    PORT
      LAYER met3 ;
        RECT 600.465 115.640 604.465 116.240 ;
    END
  END sin[2]
  PIN sin[30]
    DIRECTION INPUT ;
    USE SIGNAL ;
    ANTENNAGATEAREA 0.159000 ;
    PORT
      LAYER met3 ;
        RECT 0.000 336.640 4.000 337.240 ;
    END
  END sin[30]
  PIN sin[31]
    DIRECTION INPUT ;
    USE SIGNAL ;
    ANTENNAGATEAREA 0.196500 ;
    PORT
      LAYER met3 ;
        RECT 0.000 442.040 4.000 442.640 ;
    END
  END sin[31]
  PIN sin[3]
    DIRECTION INPUT ;
    USE SIGNAL ;
    ANTENNAGATEAREA 0.196500 ;
    PORT
      LAYER met3 ;
        RECT 600.465 119.040 604.465 119.640 ;
    END
  END sin[3]
  PIN sin[4]
    DIRECTION INPUT ;
    USE SIGNAL ;
    ANTENNAGATEAREA 0.196500 ;
    PORT
      LAYER met3 ;
        RECT 600.465 122.440 604.465 123.040 ;
    END
  END sin[4]
  PIN sin[5]
    DIRECTION INPUT ;
    USE SIGNAL ;
    ANTENNAGATEAREA 0.426000 ;
    PORT
      LAYER met3 ;
        RECT 600.465 125.840 604.465 126.440 ;
    END
  END sin[5]
  PIN sin[6]
    DIRECTION INPUT ;
    USE SIGNAL ;
    ANTENNAGATEAREA 0.213000 ;
    PORT
      LAYER met3 ;
        RECT 600.465 136.040 604.465 136.640 ;
    END
  END sin[6]
  PIN sin[7]
    DIRECTION INPUT ;
    USE SIGNAL ;
    ANTENNAGATEAREA 0.495000 ;
    PORT
      LAYER met3 ;
        RECT 600.465 139.440 604.465 140.040 ;
    END
  END sin[7]
  PIN sin[8]
    DIRECTION INPUT ;
    USE SIGNAL ;
    ANTENNAGATEAREA 0.196500 ;
    PORT
      LAYER met3 ;
        RECT 600.465 142.840 604.465 143.440 ;
    END
  END sin[8]
  PIN sin[9]
    DIRECTION INPUT ;
    USE SIGNAL ;
    ANTENNAGATEAREA 0.213000 ;
    PORT
      LAYER met3 ;
        RECT 600.465 163.240 604.465 163.840 ;
    END
  END sin[9]
  PIN start
    DIRECTION INPUT ;
    USE SIGNAL ;
    ANTENNAGATEAREA 0.213000 ;
    PORT
      LAYER met3 ;
        RECT 600.465 323.040 604.465 323.640 ;
    END
  END start
  OBS
      LAYER li1 ;
        RECT 5.520 10.795 598.920 603.925 ;
      LAYER met1 ;
        RECT 4.670 9.900 599.770 604.080 ;
      LAYER met2 ;
        RECT 4.690 610.905 296.050 611.730 ;
        RECT 296.890 610.905 308.930 611.730 ;
        RECT 309.770 610.905 325.030 611.730 ;
        RECT 325.870 610.905 344.350 611.730 ;
        RECT 345.190 610.905 354.010 611.730 ;
        RECT 354.850 610.905 370.110 611.730 ;
        RECT 370.950 610.905 386.210 611.730 ;
        RECT 387.050 610.905 399.090 611.730 ;
        RECT 399.930 610.905 415.190 611.730 ;
        RECT 416.030 610.905 428.070 611.730 ;
        RECT 428.910 610.905 440.950 611.730 ;
        RECT 441.790 610.905 457.050 611.730 ;
        RECT 457.890 610.905 473.150 611.730 ;
        RECT 473.990 610.905 482.810 611.730 ;
        RECT 483.650 610.905 495.690 611.730 ;
        RECT 496.530 610.905 508.570 611.730 ;
        RECT 509.410 610.905 521.450 611.730 ;
        RECT 522.290 610.905 537.550 611.730 ;
        RECT 538.390 610.905 553.650 611.730 ;
        RECT 554.490 610.905 569.750 611.730 ;
        RECT 570.590 610.905 582.630 611.730 ;
        RECT 583.470 610.905 599.750 611.730 ;
        RECT 4.690 4.280 599.750 610.905 ;
        RECT 4.690 3.670 15.910 4.280 ;
        RECT 16.750 3.670 19.130 4.280 ;
        RECT 19.970 3.670 22.350 4.280 ;
        RECT 23.190 3.670 25.570 4.280 ;
        RECT 26.410 3.670 28.790 4.280 ;
        RECT 29.630 3.670 32.010 4.280 ;
        RECT 32.850 3.670 35.230 4.280 ;
        RECT 36.070 3.670 38.450 4.280 ;
        RECT 39.290 3.670 41.670 4.280 ;
        RECT 42.510 3.670 44.890 4.280 ;
        RECT 45.730 3.670 48.110 4.280 ;
        RECT 48.950 3.670 51.330 4.280 ;
        RECT 52.170 3.670 54.550 4.280 ;
        RECT 55.390 3.670 57.770 4.280 ;
        RECT 58.610 3.670 60.990 4.280 ;
        RECT 61.830 3.670 64.210 4.280 ;
        RECT 65.050 3.670 67.430 4.280 ;
        RECT 68.270 3.670 70.650 4.280 ;
        RECT 71.490 3.670 73.870 4.280 ;
        RECT 74.710 3.670 77.090 4.280 ;
        RECT 77.930 3.670 80.310 4.280 ;
        RECT 81.150 3.670 83.530 4.280 ;
        RECT 84.370 3.670 86.750 4.280 ;
        RECT 87.590 3.670 89.970 4.280 ;
        RECT 90.810 3.670 93.190 4.280 ;
        RECT 94.030 3.670 96.410 4.280 ;
        RECT 97.250 3.670 599.750 4.280 ;
      LAYER met3 ;
        RECT 3.990 582.440 600.465 604.005 ;
        RECT 4.400 581.040 600.465 582.440 ;
        RECT 3.990 579.040 600.465 581.040 ;
        RECT 4.400 577.640 600.465 579.040 ;
        RECT 3.990 575.640 600.465 577.640 ;
        RECT 4.400 574.240 600.465 575.640 ;
        RECT 3.990 572.240 600.465 574.240 ;
        RECT 4.400 570.840 600.465 572.240 ;
        RECT 3.990 568.840 600.465 570.840 ;
        RECT 4.400 567.440 600.465 568.840 ;
        RECT 3.990 565.440 600.465 567.440 ;
        RECT 4.400 564.040 600.465 565.440 ;
        RECT 3.990 562.040 600.465 564.040 ;
        RECT 4.400 560.640 600.465 562.040 ;
        RECT 3.990 558.640 600.465 560.640 ;
        RECT 4.400 557.240 600.465 558.640 ;
        RECT 3.990 555.240 600.465 557.240 ;
        RECT 4.400 553.840 600.465 555.240 ;
        RECT 3.990 551.840 600.465 553.840 ;
        RECT 4.400 550.440 600.465 551.840 ;
        RECT 3.990 548.440 600.465 550.440 ;
        RECT 4.400 547.040 600.465 548.440 ;
        RECT 3.990 545.040 600.465 547.040 ;
        RECT 4.400 543.640 600.465 545.040 ;
        RECT 3.990 541.640 600.465 543.640 ;
        RECT 4.400 540.240 600.465 541.640 ;
        RECT 3.990 538.240 600.465 540.240 ;
        RECT 4.400 536.840 600.465 538.240 ;
        RECT 3.990 534.840 600.465 536.840 ;
        RECT 4.400 533.440 600.465 534.840 ;
        RECT 3.990 531.440 600.465 533.440 ;
        RECT 4.400 530.040 600.465 531.440 ;
        RECT 3.990 528.040 600.465 530.040 ;
        RECT 4.400 526.640 600.465 528.040 ;
        RECT 3.990 524.640 600.465 526.640 ;
        RECT 4.400 523.240 600.465 524.640 ;
        RECT 3.990 521.240 600.465 523.240 ;
        RECT 4.400 519.840 600.465 521.240 ;
        RECT 3.990 517.840 600.465 519.840 ;
        RECT 4.400 516.440 600.465 517.840 ;
        RECT 3.990 514.440 600.465 516.440 ;
        RECT 4.400 513.040 600.465 514.440 ;
        RECT 3.990 511.040 600.465 513.040 ;
        RECT 4.400 509.640 600.465 511.040 ;
        RECT 3.990 507.640 600.465 509.640 ;
        RECT 4.400 506.240 600.465 507.640 ;
        RECT 3.990 504.240 600.465 506.240 ;
        RECT 4.400 502.840 600.465 504.240 ;
        RECT 3.990 500.840 600.465 502.840 ;
        RECT 4.400 499.440 600.465 500.840 ;
        RECT 3.990 497.440 600.465 499.440 ;
        RECT 4.400 496.040 600.465 497.440 ;
        RECT 3.990 494.040 600.465 496.040 ;
        RECT 4.400 492.640 600.465 494.040 ;
        RECT 3.990 490.640 600.465 492.640 ;
        RECT 4.400 489.240 600.465 490.640 ;
        RECT 3.990 487.240 600.465 489.240 ;
        RECT 4.400 485.840 600.465 487.240 ;
        RECT 3.990 483.840 600.465 485.840 ;
        RECT 4.400 482.440 600.465 483.840 ;
        RECT 3.990 480.440 600.465 482.440 ;
        RECT 4.400 479.040 600.465 480.440 ;
        RECT 3.990 477.040 600.465 479.040 ;
        RECT 4.400 475.640 600.465 477.040 ;
        RECT 3.990 473.640 600.465 475.640 ;
        RECT 4.400 472.240 600.465 473.640 ;
        RECT 3.990 470.240 600.465 472.240 ;
        RECT 4.400 468.840 600.465 470.240 ;
        RECT 3.990 446.440 600.465 468.840 ;
        RECT 3.990 445.040 600.065 446.440 ;
        RECT 3.990 443.040 600.465 445.040 ;
        RECT 4.400 441.640 600.065 443.040 ;
        RECT 3.990 439.640 600.465 441.640 ;
        RECT 3.990 438.240 600.065 439.640 ;
        RECT 3.990 436.240 600.465 438.240 ;
        RECT 3.990 434.840 600.065 436.240 ;
        RECT 3.990 432.840 600.465 434.840 ;
        RECT 3.990 431.440 600.065 432.840 ;
        RECT 3.990 429.440 600.465 431.440 ;
        RECT 3.990 428.040 600.065 429.440 ;
        RECT 3.990 426.040 600.465 428.040 ;
        RECT 4.400 424.640 600.065 426.040 ;
        RECT 3.990 422.640 600.465 424.640 ;
        RECT 3.990 421.240 600.065 422.640 ;
        RECT 3.990 419.240 600.465 421.240 ;
        RECT 3.990 417.840 600.065 419.240 ;
        RECT 3.990 415.840 600.465 417.840 ;
        RECT 3.990 414.440 600.065 415.840 ;
        RECT 3.990 412.440 600.465 414.440 ;
        RECT 3.990 411.040 600.065 412.440 ;
        RECT 3.990 409.040 600.465 411.040 ;
        RECT 3.990 407.640 600.065 409.040 ;
        RECT 3.990 405.640 600.465 407.640 ;
        RECT 3.990 404.240 600.065 405.640 ;
        RECT 3.990 402.240 600.465 404.240 ;
        RECT 4.400 400.840 600.065 402.240 ;
        RECT 3.990 398.840 600.465 400.840 ;
        RECT 4.400 397.440 600.065 398.840 ;
        RECT 3.990 395.440 600.465 397.440 ;
        RECT 4.400 394.040 600.065 395.440 ;
        RECT 3.990 392.040 600.465 394.040 ;
        RECT 4.400 390.640 600.065 392.040 ;
        RECT 3.990 388.640 600.465 390.640 ;
        RECT 4.400 387.240 600.065 388.640 ;
        RECT 3.990 385.240 600.465 387.240 ;
        RECT 4.400 383.840 600.065 385.240 ;
        RECT 3.990 381.840 600.465 383.840 ;
        RECT 4.400 380.440 600.065 381.840 ;
        RECT 3.990 378.440 600.465 380.440 ;
        RECT 4.400 377.040 600.065 378.440 ;
        RECT 3.990 375.040 600.465 377.040 ;
        RECT 4.400 373.640 600.065 375.040 ;
        RECT 3.990 371.640 600.465 373.640 ;
        RECT 3.990 370.240 600.065 371.640 ;
        RECT 3.990 368.240 600.465 370.240 ;
        RECT 3.990 366.840 600.065 368.240 ;
        RECT 3.990 364.840 600.465 366.840 ;
        RECT 3.990 363.440 600.065 364.840 ;
        RECT 3.990 361.440 600.465 363.440 ;
        RECT 3.990 360.040 600.065 361.440 ;
        RECT 3.990 358.040 600.465 360.040 ;
        RECT 3.990 356.640 600.065 358.040 ;
        RECT 3.990 354.640 600.465 356.640 ;
        RECT 3.990 353.240 600.065 354.640 ;
        RECT 3.990 351.240 600.465 353.240 ;
        RECT 3.990 349.840 600.065 351.240 ;
        RECT 3.990 347.840 600.465 349.840 ;
        RECT 4.400 346.440 600.065 347.840 ;
        RECT 3.990 344.440 600.465 346.440 ;
        RECT 4.400 343.040 600.065 344.440 ;
        RECT 3.990 341.040 600.465 343.040 ;
        RECT 4.400 339.640 600.065 341.040 ;
        RECT 3.990 337.640 600.465 339.640 ;
        RECT 4.400 336.240 600.065 337.640 ;
        RECT 3.990 334.240 600.465 336.240 ;
        RECT 3.990 332.840 600.065 334.240 ;
        RECT 3.990 330.840 600.465 332.840 ;
        RECT 4.400 329.440 600.065 330.840 ;
        RECT 3.990 327.440 600.465 329.440 ;
        RECT 3.990 326.040 600.065 327.440 ;
        RECT 3.990 324.040 600.465 326.040 ;
        RECT 4.400 322.640 600.065 324.040 ;
        RECT 3.990 320.640 600.465 322.640 ;
        RECT 4.400 319.240 600.065 320.640 ;
        RECT 3.990 317.240 600.465 319.240 ;
        RECT 4.400 315.840 600.065 317.240 ;
        RECT 3.990 313.840 600.465 315.840 ;
        RECT 4.400 312.440 600.065 313.840 ;
        RECT 3.990 310.440 600.465 312.440 ;
        RECT 4.400 309.040 600.065 310.440 ;
        RECT 3.990 307.040 600.465 309.040 ;
        RECT 4.400 305.640 600.065 307.040 ;
        RECT 3.990 303.640 600.465 305.640 ;
        RECT 4.400 302.240 600.065 303.640 ;
        RECT 3.990 300.240 600.465 302.240 ;
        RECT 4.400 298.840 600.065 300.240 ;
        RECT 3.990 296.840 600.465 298.840 ;
        RECT 4.400 295.440 600.065 296.840 ;
        RECT 3.990 293.440 600.465 295.440 ;
        RECT 4.400 292.040 600.065 293.440 ;
        RECT 3.990 290.040 600.465 292.040 ;
        RECT 4.400 288.640 600.065 290.040 ;
        RECT 3.990 286.640 600.465 288.640 ;
        RECT 4.400 285.240 600.065 286.640 ;
        RECT 3.990 283.240 600.465 285.240 ;
        RECT 3.990 281.840 600.065 283.240 ;
        RECT 3.990 279.840 600.465 281.840 ;
        RECT 3.990 278.440 600.065 279.840 ;
        RECT 3.990 276.440 600.465 278.440 ;
        RECT 3.990 275.040 600.065 276.440 ;
        RECT 3.990 273.040 600.465 275.040 ;
        RECT 3.990 271.640 600.065 273.040 ;
        RECT 3.990 269.640 600.465 271.640 ;
        RECT 3.990 268.240 600.065 269.640 ;
        RECT 3.990 266.240 600.465 268.240 ;
        RECT 3.990 264.840 600.065 266.240 ;
        RECT 3.990 262.840 600.465 264.840 ;
        RECT 3.990 261.440 600.065 262.840 ;
        RECT 3.990 259.440 600.465 261.440 ;
        RECT 3.990 258.040 600.065 259.440 ;
        RECT 3.990 256.040 600.465 258.040 ;
        RECT 3.990 254.640 600.065 256.040 ;
        RECT 3.990 252.640 600.465 254.640 ;
        RECT 3.990 251.240 600.065 252.640 ;
        RECT 3.990 249.240 600.465 251.240 ;
        RECT 3.990 247.840 600.065 249.240 ;
        RECT 3.990 164.240 600.465 247.840 ;
        RECT 3.990 162.840 600.065 164.240 ;
        RECT 3.990 160.840 600.465 162.840 ;
        RECT 3.990 159.440 600.065 160.840 ;
        RECT 3.990 157.440 600.465 159.440 ;
        RECT 3.990 156.040 600.065 157.440 ;
        RECT 3.990 154.040 600.465 156.040 ;
        RECT 3.990 152.640 600.065 154.040 ;
        RECT 3.990 150.640 600.465 152.640 ;
        RECT 3.990 149.240 600.065 150.640 ;
        RECT 3.990 147.240 600.465 149.240 ;
        RECT 3.990 145.840 600.065 147.240 ;
        RECT 3.990 143.840 600.465 145.840 ;
        RECT 3.990 142.440 600.065 143.840 ;
        RECT 3.990 140.440 600.465 142.440 ;
        RECT 3.990 139.040 600.065 140.440 ;
        RECT 3.990 137.040 600.465 139.040 ;
        RECT 3.990 135.640 600.065 137.040 ;
        RECT 3.990 133.640 600.465 135.640 ;
        RECT 3.990 132.240 600.065 133.640 ;
        RECT 3.990 130.240 600.465 132.240 ;
        RECT 3.990 128.840 600.065 130.240 ;
        RECT 3.990 126.840 600.465 128.840 ;
        RECT 3.990 125.440 600.065 126.840 ;
        RECT 3.990 123.440 600.465 125.440 ;
        RECT 3.990 122.040 600.065 123.440 ;
        RECT 3.990 120.040 600.465 122.040 ;
        RECT 3.990 118.640 600.065 120.040 ;
        RECT 3.990 116.640 600.465 118.640 ;
        RECT 3.990 115.240 600.065 116.640 ;
        RECT 3.990 113.240 600.465 115.240 ;
        RECT 3.990 111.840 600.065 113.240 ;
        RECT 3.990 109.840 600.465 111.840 ;
        RECT 3.990 108.440 600.065 109.840 ;
        RECT 3.990 106.440 600.465 108.440 ;
        RECT 3.990 105.040 600.065 106.440 ;
        RECT 3.990 103.040 600.465 105.040 ;
        RECT 3.990 101.640 600.065 103.040 ;
        RECT 3.990 99.640 600.465 101.640 ;
        RECT 3.990 98.240 600.065 99.640 ;
        RECT 3.990 96.240 600.465 98.240 ;
        RECT 3.990 94.840 600.065 96.240 ;
        RECT 3.990 79.240 600.465 94.840 ;
        RECT 3.990 77.840 600.065 79.240 ;
        RECT 3.990 75.840 600.465 77.840 ;
        RECT 3.990 74.440 600.065 75.840 ;
        RECT 3.990 69.040 600.465 74.440 ;
        RECT 3.990 67.640 600.065 69.040 ;
        RECT 3.990 65.640 600.465 67.640 ;
        RECT 3.990 64.240 600.065 65.640 ;
        RECT 3.990 62.240 600.465 64.240 ;
        RECT 3.990 60.840 600.065 62.240 ;
        RECT 3.990 58.840 600.465 60.840 ;
        RECT 3.990 57.440 600.065 58.840 ;
        RECT 3.990 55.440 600.465 57.440 ;
        RECT 3.990 54.040 600.065 55.440 ;
        RECT 3.990 10.715 600.465 54.040 ;
      LAYER met4 ;
        RECT 10.415 11.735 20.640 600.945 ;
        RECT 23.040 11.735 23.940 600.945 ;
        RECT 26.340 11.735 174.240 600.945 ;
        RECT 176.640 11.735 177.540 600.945 ;
        RECT 179.940 11.735 327.840 600.945 ;
        RECT 330.240 11.735 331.140 600.945 ;
        RECT 333.540 11.735 481.440 600.945 ;
        RECT 483.840 11.735 484.740 600.945 ;
        RECT 487.140 11.735 593.105 600.945 ;
      LAYER met5 ;
        RECT 98.100 492.770 347.180 570.300 ;
        RECT 98.100 339.590 347.180 484.670 ;
        RECT 98.100 186.410 347.180 331.490 ;
        RECT 98.100 174.300 347.180 178.310 ;
  END
END inverse_park
END LIBRARY

